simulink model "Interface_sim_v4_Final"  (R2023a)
settings: Solver=FixedStepAuto  StartTime=0  StopTime=stop_time  FixedStep=step  RelTol=1e-3
InitFcn:
  | spec_data
StopFcn:
  | stop_fcn
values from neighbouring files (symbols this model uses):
  Air_density = 1.205    [spec_data.m]
  B_CAP = 7000    [spec_data.m]
  CdA = 0.13    [spec_data.m]
  distance_offset = 0    [spec_data.m]
  Gravity = 9.80665    [spec_data.m]
  meffi = 0.9    [spec_data.m]
  Motor_force_limit = 100    [spec_data.m]
  Motor_power_limit = 10000    [spec_data.m]
  Target_speed = 55    [spec_data.m]
  Time_offset = 9*3600    (= 32400)    [spec_data.m]    (also in Sim_set.m = 0)
  tyre_u = 0.015    [spec_data.m]
  weight = 250    [spec_data.m]
undefined symbols (not defined in the file or in its folder): magnitude, map_data
libraries: slpidlib x1, simulink x1

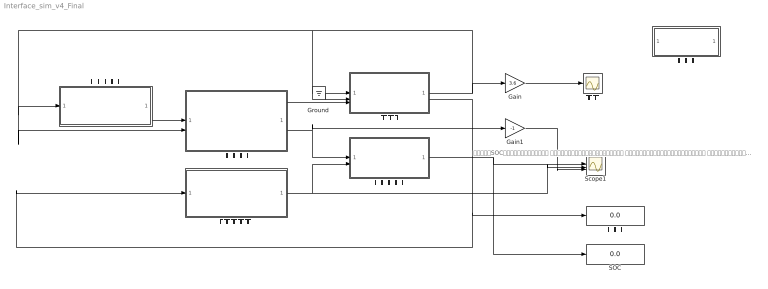
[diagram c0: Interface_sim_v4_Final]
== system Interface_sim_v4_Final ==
  note: 初期では、SOC、発電電力、モーター消費が 表示されています。午前中は、ソーラーの発電 が弱く、バッテリーのＳＯＣが減少していますが、 時間の経過につれ、発電電力が高くなり、 SOCの減少スピードが緩くなるのが確認できます
  Gain : Gain  Gain=3.6
  Gain1 : Gain  Gain=-1
  Ground : Ground
  SOC : Display
  Scope1 : Scope  NumInputPorts=3
  ソーラー発電モデル : Subsystem
  データの保存 : Subsystem
  ドライバーモデル : Subsystem
  バッテリーモデル : Subsystem
  モーターモデル : Subsystem
  走行距離 : Display
  車両モデル : Subsystem
  車両速度 : Scope
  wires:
  車両モデル/1(V_Speed) -> Gain/1, 車両モデル/1(Vehicle speed), ドライバーモデル/1(V_Speed), モーターモデル/2(Vehicle speed)
  モーターモデル/1(Motor force) -> 車両モデル/3(Motor force)
  Gain/1 -> 車両速度/1
  ドライバーモデル/1(Power demand) -> モーターモデル/1(Power demand)
  モーターモデル/2(Motor e-power) -> バッテリーモデル/1(Motro e-power), Gain1/1
  バッテリーモデル/1(SOC) -> SOC/1, Scope1/1
  Ground/1 -> 車両モデル/2(Slope angle)
  車両モデル/2(Distance) -> 走行距離/1, ソーラー発電モデル/1(Distance)
  ソーラー発電モデル/1(Solar Power) -> Scope1/2, バッテリーモデル/2(Solar power)
  Gain1/1 -> Scope1/3

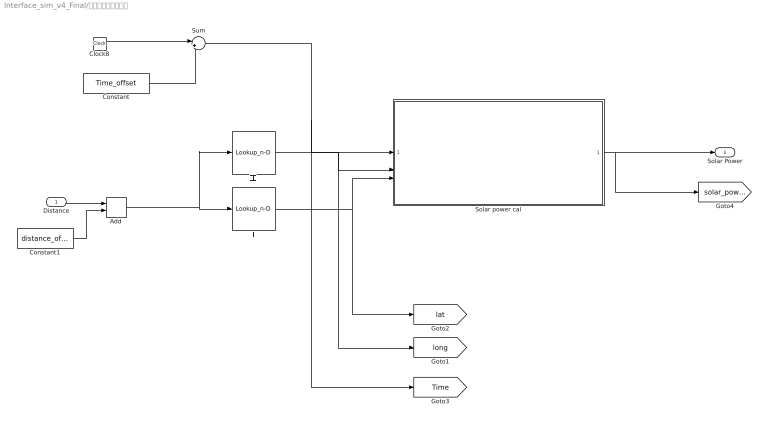
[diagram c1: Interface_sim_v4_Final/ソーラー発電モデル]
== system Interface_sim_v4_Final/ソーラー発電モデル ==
  Distance : Inport
  Add : Sum
  Clock8 : Clock
  Constant : Constant  Value=Time_offset
  Constant1 : Constant  Value=distance_offset
  Solar power cal : MATLAB Function  TreatAsAtomicUnit=on
  Sum : Sum  Inputs=|++
  経度 : Lookup_n-D  NumberOfTableDimensions=1  BreakpointsForDimension1=map_data.distance  Table=map_data.Lat  InternalRulePriority=Speed  RndMeth=Simplest
  緯度 : Lookup_n-D  NumberOfTableDimensions=1  BreakpointsForDimension1=map_data.distance  Table=map_data.Lon  InternalRulePriority=Speed  RndMeth=Simplest
  Solar Power : Outport
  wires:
  Add/1 -> 緯度/1, 経度/1
  経度/1 -> Solar power cal/3(LAT), [lat]
  Solar power cal/1(Solar_power) -> Solar Power/1, [solar_power]
  Sum/1 -> [Time], Solar power cal/1(Time)
  緯度/1 -> Solar power cal/2(LON), [long]
  Clock8/1 -> Sum/1
  Constant/1 -> Sum/2
  Constant1/1 -> Add/2
  Distance/1 -> Add/1

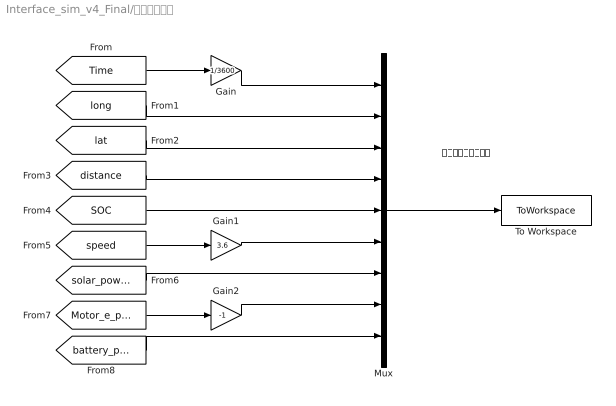
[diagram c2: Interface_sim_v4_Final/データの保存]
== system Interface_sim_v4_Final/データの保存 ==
  note: 間引き１０に設定中
  Gain : Gain  Gain=1/3600
  Gain1 : Gain  Gain=3.6
  Gain2 : Gain  Gain=-1
  Mux : Mux  Inputs=9
  To Workspace : ToWorkspace  VariableName=simout  SaveFormat=Structure With Time  SampleTime=-1
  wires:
  Mux/1 -> To Workspace/1
  [Time] -> Gain/1
  [long] -> Mux/2
  [lat] -> Mux/3
  [distance] -> Mux/4
  [SOC] -> Mux/5
  [speed] -> Gain1/1
  [Motor_e_power] -> Gain2/1
  [solar_power] -> Mux/7
  [battery_power] -> Mux/9
  Gain/1 -> Mux/1
  Gain1/1 -> Mux/6
  Gain2/1 -> Mux/8

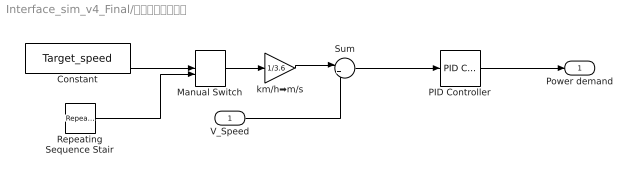
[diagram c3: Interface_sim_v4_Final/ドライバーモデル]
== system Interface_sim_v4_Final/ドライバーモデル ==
  V_Speed : Inport
  Constant : Constant  Value=Target_speed
  Manual Switch : ManualSwitch
  PID Controller : slpidlib/PID Controller  Controller=PID  Form=Parallel  TimeDomain=Discrete-time  UseExternalTs=off  SampleTime=-1  IntegratorMethod=Forward Euler  FilterMethod=Forward Euler  ControllerParametersSource=internal  P=200  I=3  UseKiTs=off  D=0  N=100  UseFilter=on  TunerSelectOption=Transfer Function Based (PID Tuner App)  InitialConditionSource=internal  InitialConditionForIntegrator=0  InitialConditionForFilter=0  DifferentiatorICPrevScaledInput=0  ExternalReset=none  TrackingMode=off  Kt=1  LimitOutput=off  SatLimitsSource=internal  UpperSaturationLimit=inf  LowerSaturationLimit=-inf  LinearizeAsGain=on  AntiWindupMode=none  Kb=1  LimitIntegrator=off  UpperIntegratorSaturationLimit=inf  LowerIntegratorSaturationLimit=-inf  POutMin=[]  POutMax=[]  IOutMin=[]  IOutMax=[]  DOutMin=[]  DOutMax=[]  NOutMin=[]  NOutMax=[]  SumOutMin=[]  SumOutMax=[]  SaturationOutMin=[]  SaturationOutMax=[]  PParamMin=[]  PParamMax=[]  IParamMin=[]  IParamMax=[]  DParamMin=[]  DParamMax=[]  NParamMin=[]  NParamMax=[]  KbParamMin=[]  KbParamMax=[]  KtParamMin=[]  KtParamMax=[]  KbOutMin=[]  KbOutMax=[]  KtOutMin=[]  KtOutMax=[]  IntegratorOutMin=[]  IntegratorOutMax=[]  FilterOutMin=[]  FilterOutMax=[]  SumI1OutMin=[]  SumI1OutMax=[]  SumI2OutMin=[]  SumI2OutMax=[]  SumI3OutMin=[]  SumI3OutMax=[]  SumI4OutMin=[]  SumI4OutMax=[]  SumDOutMin=[]  SumDOutMax=[]  DifferentiatorOutMin=[]  DifferentiatorOutMax=[]  FilterDiffOutCoefMin=[]  FilterDiffOutCoefMax=[]  ReciprocalOutMin=[]  ReciprocalOutMax=[]  SumDenOutMin=[]  SumDenOutMax=[]  SumNumOutMin=[]  SumNumOutMax=[]  DivideOutMin=[]  DivideOutMax=[]  UdiffTsProdOutMin=[]  UdiffTsProdOutMax=[]  NTsProdOutMin=[]  NTsProdOutMax=[]  UintegralTsProdOutMin=[]  UintegralTsProdOutMax=[]  UngainTsProdOutMin=[]  UngainTsProdOutMax=[]  ClampingZeroOutDataTypeStr=Inherit: Inherit via back propagation  ClampingZeroOutMin=[]  ClampingZeroOutMax=[]  FilterDenConstantOutDataTypeStr=Inherit: Inherit via back propagation  FilterDenConstantOutMin=[]  FilterDenConstantOutMax=[]  PCopyOutDataTypeStr=Inherit: Inherit via back propagation  PCopyOutMin=[]  PCopyOutMax=[]  NCopyOutDataTypeStr=Inherit: Inherit via back propagation  NCopyOutMin=[]  NCopyOutMax=[]  IntegratorContinuousStateAttributes=''  IntegratorStateMustResolveToSignalObject=off  IntegratorRTWStateStorageClass=Auto  FilterContinuousStateAttributes=''  FilterStateMustResolveToSignalObject=off  FilterRTWStateStorageClass=Auto  ParallelPVariant=InternalParameters  IdealPVariant=Disabled  IVariant=InternalParameters  DVariant=InternalParameters  IntegratorVariant=Discrete  SatVariant=Disabled  AWVariant=Passthrough  PCopyVariant=Disabled  TRVariant=Disabled  FdbkBlocksVariant=Forward  IdealPFdbkVariant=Disabled  SatFdbkVariant=Disabled  DerivativeFilterVariant=ForwardEulerFilter  NVariant=InternalParameters  NCopyVariant=Disabled  FilterICVariant=InternalICsFilter  IntegratorICVariant=InternalICs  ExternalResetVariant=Disabled  TRSumVariant=Passthrough  SumFdbkVariant=Disabled  SumVariant=Sum_PID  TsampFilterVariant=InternalTs  TsampNgainVariant=Passthrough  TsampIntegralVariant=Disabled_SignalSpec  ExternalSaturationOutDataTypeStr=Inherit: Same as second input
  Repeating Sequence Stair : simulink/Sources/Repeating Sequence Stair  OutValues=[60 30].'  tsamp=60*10  OutMin=[]  OutMax=[]  OutDataTypeStr=double  OutputDataTypeScalingMode=double  OutDataType=fixdt(0,8)  ConRadixGroup=Best Precision: Vector-wise  OutScaling=2^-12
  Sum : Sum  Inputs=|+-
  km/h➡m/s : Gain  Gain=1/3.6
  Power demand : Outport
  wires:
  PID Controller/1 -> Power demand/1
  km/h➡m/s/1 -> Sum/1
  V_Speed/1 -> Sum/2
  Sum/1 -> PID Controller/1
  Manual Switch/1 -> km/h➡m/s/1
  Constant/1 -> Manual Switch/1
  Repeating Sequence Stair/1 -> Manual Switch/2

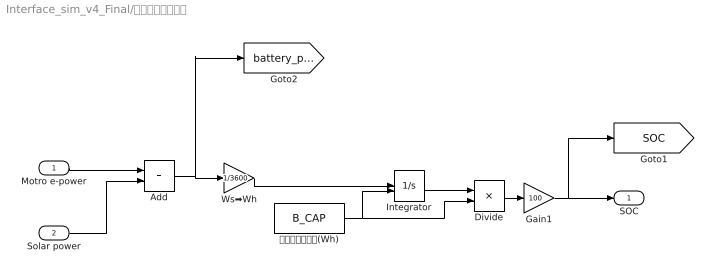
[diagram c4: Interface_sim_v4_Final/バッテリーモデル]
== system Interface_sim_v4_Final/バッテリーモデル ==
  Motro e-power : Inport
  Solar power : Inport  Port=2
  Add : Sum
  Divide : Product  Inputs=*/
  Gain1 : Gain  Gain=100
  Integrator : Integrator  InitialConditionSource=external  LimitOutput=on  UpperSaturationLimit=B_CAP  LowerSaturationLimit=0
  Ws➡Wh : Gain  Gain=1/3600
  バッテリー残量(Wh) : Constant  Value=B_CAP
  SOC : Outport
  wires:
  Motro e-power/1 -> Add/1
  Solar power/1 -> Add/2
  Add/1 -> [battery_power], Ws➡Wh/1
  Ws➡Wh/1 -> Integrator/1
  バッテリー残量(Wh)/1 -> Divide/2, Integrator/2
  Integrator/1 -> Divide/1
  Divide/1 -> Gain1/1
  Gain1/1 -> [SOC], SOC/1

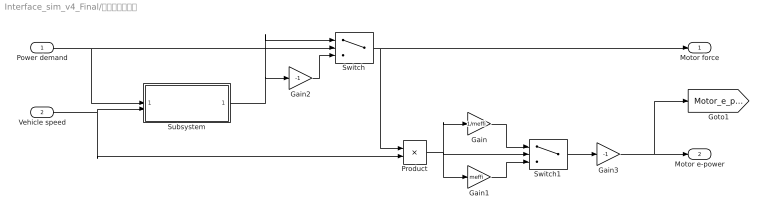
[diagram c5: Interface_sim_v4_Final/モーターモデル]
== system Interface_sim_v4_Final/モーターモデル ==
  Power demand : Inport
  Vehicle speed : Inport  Port=2
  Gain : Gain  Gain=1/meffi
  Gain1 : Gain  Gain=meffi
  Gain2 : Gain  Gain=-1
  Gain3 : Gain  Gain=-1
  Product : Product
  Subsystem : Subsystem
  Switch : Switch  Criteria=u2 > Threshold
  Switch1 : Switch  Criteria=u2 > Threshold
  Motor force : Outport
  Motor e-power : Outport  Port=2
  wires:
  Switch/1 -> Product/1, Motor force/1
  Power demand/1 -> Subsystem/1(Power_demand), Switch/2
  Gain2/1 -> Switch/3
  Subsystem/1(Motor_force) -> Switch/1, Gain2/1
  Vehicle speed/1 -> Product/2, Subsystem/2(Speed)
  Switch1/1 -> Gain3/1
  Product/1 -> Gain1/1, Gain/1, Switch1/2
  Gain1/1 -> Switch1/3
  Gain/1 -> Switch1/1
  Gain3/1 -> [Motor_e_power], Motor e-power/1

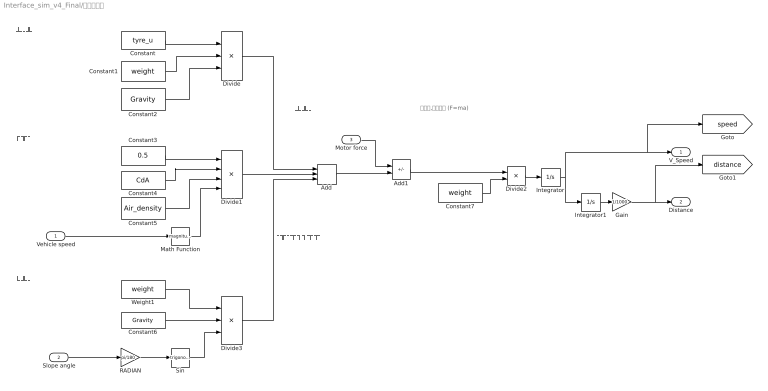
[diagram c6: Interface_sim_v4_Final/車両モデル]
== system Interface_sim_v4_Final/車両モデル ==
  note: モーター駆動力 ー 走行抵抗
  note: 空気抵抗
  note: 転がり抵抗
  note: 勾配抵抗
  note: 駆動力計算
  note: 加速度,速度計算 (F=ma)
  Vehicle speed : Inport
  Slope angle : Inport  Port=2
  Motor force : Inport  Port=3
  Add : Sum  Inputs=+++
  Add1 : Sum  Inputs=+-
  Constant : Constant  Value=tyre_u
  Constant1 : Constant  Value=weight
  Constant2 : Constant  Value=Gravity
  Constant3 : Constant  Value=0.5
  Constant4 : Constant  Value=CdA
  Constant5 : Constant  Value=Air_density
  Constant6 : Constant  Value=Gravity
  Constant7 : Constant  Value=weight
  Divide : Product  Inputs=***
  Divide1 : Product  Inputs=****
  Divide2 : Product  Inputs=*/
  Divide3 : Product  Inputs=***
  Gain : Gain  Gain=1/1000
  Integrator : Integrator
  Integrator1 : Integrator
  Math Function : Math  Operator=magnitude^2
  RADIAN : Gain  Gain=pi/180
  Sin : Trigonometry
  Weight1 : Constant  Value=weight
  V_Speed : Outport
  Distance : Outport  Port=2
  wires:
  Constant1/1 -> Divide/2
  Divide/1 -> Add/1
  Divide3/1 -> Add/3
  Divide1/1 -> Add/2
  Constant2/1 -> Divide/3
  Weight1/1 -> Divide3/1
  Math Function/1 -> Divide1/4
  RADIAN/1 -> Sin/1
  Constant4/1 -> Divide1/2
  Sin/1 -> Divide3/3
  Constant3/1 -> Divide1/1
  Constant6/1 -> Divide3/2
  Constant/1 -> Divide/1
  Constant5/1 -> Divide1/3
  Slope angle/1 -> RADIAN/1
  Vehicle speed/1 -> Math Function/1
  Add1/1 -> Divide2/1
  Constant7/1 -> Divide2/2
  Divide2/1 -> Integrator/1
  Integrator/1 -> Integrator1/1, [speed], V_Speed/1
  Motor force/1 -> Add1/1
  Add/1 -> Add1/2
  Integrator1/1 -> Gain/1
  Gain/1 -> [distance], Distance/1

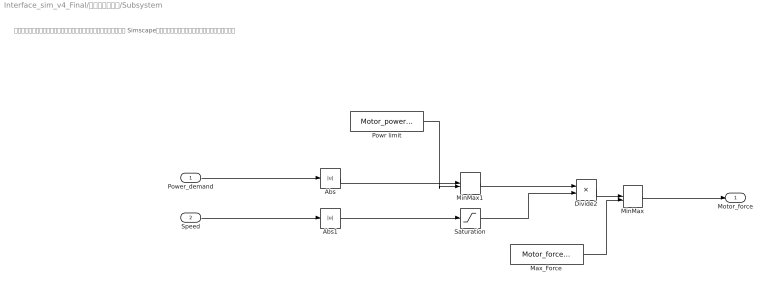
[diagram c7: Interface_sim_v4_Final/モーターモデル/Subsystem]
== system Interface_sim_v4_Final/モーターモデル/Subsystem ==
  note: シンプルに最大トルクと最大出力で制限をかけたモデルとしました。 Simscapeなどで、詳細なモデルを作成することも可能です
  Power_demand : Inport
  Speed : Inport  Port=2
  Abs : Abs
  Abs1 : Abs
  Divide2 : Product  Inputs=*/
  Max_Force : Constant  Value=Motor_force_limit
  MinMax : MinMax  Inputs=2
  MinMax1 : MinMax  Inputs=2
  Powr limit : Constant  Value=Motor_power_limit
  Saturation : Saturate  UpperLimit=inf  LowerLimit=0.01
  Motor_force : Outport
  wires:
  MinMax/1 -> Motor_force/1
  Max_Force/1 -> MinMax/2
  Abs1/1 -> Saturation/1
  Power_demand/1 -> Abs/1
  Saturation/1 -> Divide2/2
  Divide2/1 -> MinMax/1
  Abs/1 -> MinMax1/1
  MinMax1/1 -> Divide2/1
  Powr limit/1 -> MinMax1/2
  Speed/1 -> Abs1/1

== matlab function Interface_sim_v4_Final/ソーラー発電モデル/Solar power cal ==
function Solar_power = fcn(Time,LON,LAT)

%太陽定数=J0
J0 = 1367;


%大気透過率=P
P = 0.75;


%太陽電池変換効率：S_effi
S_effi=0.2;


%太陽電池面積：As
As=4;


%太陽電池傾斜角：b
b = 0;


%斜面の方位角：Y
Y = 0;


%standard time place(基準時間経度)：STP
STP = 135;        %日本：135、Darwin：142.5


%地面反射率：albedo
albedo = 0.14;


%YY、MM、DDにシミュレーションしたい年月日を入力
YY = 2023;  %年
MM = 10;  %月
DD = 20;  %日

t1 = datetime(YY,MM,DD);
t2 = datetime(YY,1,1);
dt = t1 - t2;

%年間通し日：dn
dn = days(dt); %年間通し日


%・太陽赤緯： delta（太陽光線と地球の赤道面との角度、±23°27'の範囲で変化） [単位： 度]
omega = 2*pi/365;
J = dn + 0.5;
delta= 0.33281 - 22.984*cos(omega*J) - 0.34990*cos(2*omega*J) - 0.13980*cos(3*omega*J)...
    + 3.7872*sin(omega*J) + 0.03250*sin(2*omega*J) + 0.07187*sin(3*omega*J);


%均時差： e（天球上を一定な速さで動くと考えた平均太陽と、実際の太陽との移動の差、17分未満） [単位： 時間]
e = 0.0072 * cos( omega * J ) - 0.0528*cos( 2*omega * J ) - 0.0012*cos(3 * omega * J )...
- 0.1229 * sin( omega * J ) - 0.1565*sin( 2*omega * J ) - 0.0041*sin(3 * omega * J );


%時角： t [単位： 度]
T = (Time/3600) + (LAT - STP)/15 + e;
t = 15 * T - 180;


%太陽高度(仰角)：h
h = asin(sin(deg2rad(LON))*sin(deg2rad(delta)) + cos(deg2rad(LON))*cos(deg2rad(delta))*cos(deg2rad(t)));


%方位角： A（北 = 0, 東 = 90, 南 = 180, 西 = 270°）
sinA = cos(deg2rad (delta)) * sin(deg2rad(t))/cos(h);

cosA = (sin(h) * sin(deg2rad(LON)) - sin(deg2rad(delta))) / cos(h) / cos(deg2rad(LON));

A = atan2(sinA, cosA) + pi;


%法線面直達日射：Jd
if h < 0
    h = 0;
end


    Jd = J0 * P^csc(h);
%水平面散乱日射数
Js = J0 * ( 1-P^csc(h) ) * sin( h ) / ( 2 * (1-1.4 * log(P)));


%水平面全天日射：Jh
Jh = Jd * sin(h) + Js;


%傾斜面直達日射：Hd
COSthetaA = sin(h)*cos(deg2rad(b)) + cos(h).*sin(deg2rad(b)).*cos(deg2rad(Y)-A);
COSthetaZ = sin(deg2rad(LON))*sin(deg2rad(delta))+cos(deg2rad(LON))*cos(deg2rad(delta))*cos(deg2rad(omega));

Hd = Jd * sin(h) * COSthetaA / COSthetaZ;


%傾斜面散乱日射：Hs
Hs=Js * (1 + cos(deg2rad(b))) / 2;


%傾斜面反射日射：Hr
Hr=Jh * albedo * (1 - cos(deg2rad(b))) / 2;


%傾斜面全天日射
H=Hd+Hs+Hr;

%発電電力量
Pv=H*S_effi*As;
Solar_power = Pv;
